VERSION 5.4 ;
NAMESCASESENSITIVE ON ;
BUSBITCHARS "[]" ;
DIVIDERCHAR "/" ;
UNITS
  DATABASE MICRONS 2000 ;
END UNITS
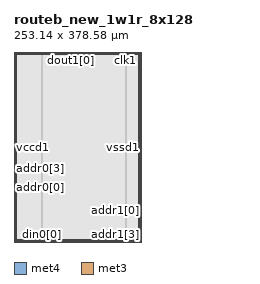
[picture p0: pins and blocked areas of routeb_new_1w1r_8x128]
MACRO routeb_new_1w1r_8x128
   CLASS BLOCK ;
   SIZE 253.14 BY 378.58 ;
   SYMMETRY X Y R90 ;
   PIN din0[0]
      DIRECTION INPUT ;
      PORT
         LAYER met4 ;
         RECT  56.02 0.0 56.4 0.38 ;
      END
   END din0[0]
   PIN din0[1]
      DIRECTION INPUT ;
      PORT
         LAYER met4 ;
         RECT  61.86 0.0 62.24 0.38 ;
      END
   END din0[1]
   PIN din0[2]
      DIRECTION INPUT ;
      PORT
         LAYER met4 ;
         RECT  67.7 0.0 68.08 0.38 ;
      END
   END din0[2]
   PIN din0[3]
      DIRECTION INPUT ;
      PORT
         LAYER met4 ;
         RECT  73.54 0.0 73.92 0.38 ;
      END
   END din0[3]
   PIN din0[4]
      DIRECTION INPUT ;
      PORT
         LAYER met4 ;
         RECT  79.38 0.0 79.76 0.38 ;
      END
   END din0[4]
   PIN din0[5]
      DIRECTION INPUT ;
      PORT
         LAYER met4 ;
         RECT  85.22 0.0 85.6 0.38 ;
      END
   END din0[5]
   PIN din0[6]
      DIRECTION INPUT ;
      PORT
         LAYER met4 ;
         RECT  91.06 0.0 91.44 0.38 ;
      END
   END din0[6]
   PIN din0[7]
      DIRECTION INPUT ;
      PORT
         LAYER met4 ;
         RECT  96.9 0.0 97.28 0.38 ;
      END
   END din0[7]
   PIN addr0[0]
      DIRECTION INPUT ;
      PORT
         LAYER met3 ;
         RECT  0.0 108.68 0.38 109.06 ;
      END
   END addr0[0]
   PIN addr0[1]
      DIRECTION INPUT ;
      PORT
         LAYER met3 ;
         RECT  0.0 117.18 0.38 117.56 ;
      END
   END addr0[1]
   PIN addr0[2]
      DIRECTION INPUT ;
      PORT
         LAYER met3 ;
         RECT  0.0 122.82 0.38 123.2 ;
      END
   END addr0[2]
   PIN addr0[3]
      DIRECTION INPUT ;
      PORT
         LAYER met3 ;
         RECT  0.0 131.32 0.38 131.7 ;
      END
   END addr0[3]
   PIN addr0[4]
      DIRECTION INPUT ;
      PORT
         LAYER met3 ;
         RECT  0.0 136.96 0.38 137.34 ;
      END
   END addr0[4]
   PIN addr0[5]
      DIRECTION INPUT ;
      PORT
         LAYER met3 ;
         RECT  0.0 145.46 0.38 145.84 ;
      END
   END addr0[5]
   PIN addr0[6]
      DIRECTION INPUT ;
      PORT
         LAYER met3 ;
         RECT  0.0 151.1 0.38 151.48 ;
      END
   END addr0[6]
   PIN addr1[0]
      DIRECTION INPUT ;
      PORT
         LAYER met3 ;
         RECT  252.76 63.54 253.14 63.92 ;
      END
   END addr1[0]
   PIN addr1[1]
      DIRECTION INPUT ;
      PORT
         LAYER met3 ;
         RECT  252.76 55.04 253.14 55.42 ;
      END
   END addr1[1]
   PIN addr1[2]
      DIRECTION INPUT ;
      PORT
         LAYER met3 ;
         RECT  252.76 49.4 253.14 49.78 ;
      END
   END addr1[2]
   PIN addr1[3]
      DIRECTION INPUT ;
      PORT
         LAYER met4 ;
         RECT  209.96 0.0 210.34 0.38 ;
      END
   END addr1[3]
   PIN addr1[4]
      DIRECTION INPUT ;
      PORT
         LAYER met4 ;
         RECT  206.985 0.0 207.365 0.38 ;
      END
   END addr1[4]
   PIN addr1[5]
      DIRECTION INPUT ;
      PORT
         LAYER met4 ;
         RECT  207.675 0.0 208.055 0.38 ;
      END
   END addr1[5]
   PIN addr1[6]
      DIRECTION INPUT ;
      PORT
         LAYER met4 ;
         RECT  208.42 0.0 208.8 0.38 ;
      END
   END addr1[6]
   PIN csb0
      DIRECTION INPUT ;
      PORT
         LAYER met3 ;
         RECT  0.0 14.87 0.38 15.25 ;
      END
   END csb0
   PIN csb1
      DIRECTION INPUT ;
      PORT
         LAYER met3 ;
         RECT  252.76 363.33 253.14 363.71 ;
      END
   END csb1
   PIN clk0
      DIRECTION INPUT ;
      PORT
         LAYER met4 ;
         RECT  30.26 0.0 30.64 0.38 ;
      END
   END clk0
   PIN clk1
      DIRECTION INPUT ;
      PORT
         LAYER met4 ;
         RECT  222.5 378.2 222.88 378.58 ;
      END
   END clk1
   PIN dout1[0]
      DIRECTION OUTPUT ;
      PORT
         LAYER met4 ;
         RECT  114.325 378.2 114.705 378.58 ;
      END
   END dout1[0]
   PIN dout1[1]
      DIRECTION OUTPUT ;
      PORT
         LAYER met4 ;
         RECT  119.295 378.2 119.675 378.58 ;
      END
   END dout1[1]
   PIN dout1[2]
      DIRECTION OUTPUT ;
      PORT
         LAYER met4 ;
         RECT  120.565 378.2 120.945 378.58 ;
      END
   END dout1[2]
   PIN dout1[3]
      DIRECTION OUTPUT ;
      PORT
         LAYER met4 ;
         RECT  125.535 378.2 125.915 378.58 ;
      END
   END dout1[3]
   PIN dout1[4]
      DIRECTION OUTPUT ;
      PORT
         LAYER met4 ;
         RECT  126.805 378.2 127.185 378.58 ;
      END
   END dout1[4]
   PIN dout1[5]
      DIRECTION OUTPUT ;
      PORT
         LAYER met4 ;
         RECT  131.775 378.2 132.155 378.58 ;
      END
   END dout1[5]
   PIN dout1[6]
      DIRECTION OUTPUT ;
      PORT
         LAYER met4 ;
         RECT  133.045 378.2 133.425 378.58 ;
      END
   END dout1[6]
   PIN dout1[7]
      DIRECTION OUTPUT ;
      PORT
         LAYER met4 ;
         RECT  138.015 378.2 138.395 378.58 ;
      END
   END dout1[7]
   PIN vccd1
      DIRECTION INOUT ;
      USE POWER ; 
      SHAPE ABUTMENT ; 
      PORT
         LAYER met3 ;
         RECT  0.0 376.84 253.14 378.58 ;
         LAYER met4 ;
         RECT  0.0 0.0 1.74 378.58 ;
         LAYER met4 ;
         RECT  251.4 0.0 253.14 378.58 ;
         LAYER met3 ;
         RECT  0.0 0.0 253.14 1.74 ;
      END
   END vccd1
   PIN vssd1
      DIRECTION INOUT ;
      USE GROUND ; 
      SHAPE ABUTMENT ; 
      PORT
         LAYER met3 ;
         RECT  3.48 3.48 249.66 5.22 ;
         LAYER met4 ;
         RECT  247.92 3.48 249.66 375.1 ;
         LAYER met3 ;
         RECT  3.48 373.36 249.66 375.1 ;
         LAYER met4 ;
         RECT  3.48 3.48 5.22 375.1 ;
      END
   END vssd1
   OBS
   LAYER  met1 ;
      RECT  0.62 0.62 252.52 377.96 ;
   LAYER  met2 ;
      RECT  0.62 0.62 252.52 377.96 ;
   LAYER  met3 ;
      RECT  0.98 108.08 252.52 109.66 ;
      RECT  0.62 109.66 0.98 116.58 ;
      RECT  0.62 118.16 0.98 122.22 ;
      RECT  0.62 123.8 0.98 130.72 ;
      RECT  0.62 132.3 0.98 136.36 ;
      RECT  0.62 137.94 0.98 144.86 ;
      RECT  0.62 146.44 0.98 150.5 ;
      RECT  0.98 62.94 252.16 64.52 ;
      RECT  0.98 64.52 252.16 108.08 ;
      RECT  252.16 64.52 252.52 108.08 ;
      RECT  252.16 56.02 252.52 62.94 ;
      RECT  252.16 50.38 252.52 54.44 ;
      RECT  0.62 15.85 0.98 108.08 ;
      RECT  0.98 109.66 252.16 362.73 ;
      RECT  0.98 362.73 252.16 364.31 ;
      RECT  252.16 109.66 252.52 362.73 ;
      RECT  0.62 152.08 0.98 376.24 ;
      RECT  252.16 364.31 252.52 376.24 ;
      RECT  252.16 2.34 252.52 48.8 ;
      RECT  0.62 2.34 0.98 14.27 ;
      RECT  0.98 2.34 2.88 2.88 ;
      RECT  0.98 2.88 2.88 5.82 ;
      RECT  0.98 5.82 2.88 62.94 ;
      RECT  2.88 2.34 250.26 2.88 ;
      RECT  2.88 5.82 250.26 62.94 ;
      RECT  250.26 2.34 252.16 2.88 ;
      RECT  250.26 2.88 252.16 5.82 ;
      RECT  250.26 5.82 252.16 62.94 ;
      RECT  0.98 364.31 2.88 372.76 ;
      RECT  0.98 372.76 2.88 375.7 ;
      RECT  0.98 375.7 2.88 376.24 ;
      RECT  2.88 364.31 250.26 372.76 ;
      RECT  2.88 375.7 250.26 376.24 ;
      RECT  250.26 364.31 252.16 372.76 ;
      RECT  250.26 372.76 252.16 375.7 ;
      RECT  250.26 375.7 252.16 376.24 ;
   LAYER  met4 ;
      RECT  55.42 0.98 57.0 377.96 ;
      RECT  57.0 0.62 61.26 0.98 ;
      RECT  62.84 0.62 67.1 0.98 ;
      RECT  68.68 0.62 72.94 0.98 ;
      RECT  74.52 0.62 78.78 0.98 ;
      RECT  80.36 0.62 84.62 0.98 ;
      RECT  86.2 0.62 90.46 0.98 ;
      RECT  92.04 0.62 96.3 0.98 ;
      RECT  97.88 0.62 206.385 0.98 ;
      RECT  31.24 0.62 55.42 0.98 ;
      RECT  57.0 0.98 221.9 377.6 ;
      RECT  221.9 0.98 223.48 377.6 ;
      RECT  57.0 377.6 113.725 377.96 ;
      RECT  115.305 377.6 118.695 377.96 ;
      RECT  121.545 377.6 124.935 377.96 ;
      RECT  127.785 377.6 131.175 377.96 ;
      RECT  134.025 377.6 137.415 377.96 ;
      RECT  138.995 377.6 221.9 377.96 ;
      RECT  2.34 0.62 29.66 0.98 ;
      RECT  210.94 0.62 250.8 0.98 ;
      RECT  223.48 377.6 250.8 377.96 ;
      RECT  223.48 0.98 247.32 2.88 ;
      RECT  223.48 2.88 247.32 375.7 ;
      RECT  223.48 375.7 247.32 377.6 ;
      RECT  247.32 0.98 250.26 2.88 ;
      RECT  247.32 375.7 250.26 377.6 ;
      RECT  250.26 0.98 250.8 2.88 ;
      RECT  250.26 2.88 250.8 375.7 ;
      RECT  250.26 375.7 250.8 377.6 ;
      RECT  2.34 0.98 2.88 2.88 ;
      RECT  2.34 2.88 2.88 375.7 ;
      RECT  2.34 375.7 2.88 377.96 ;
      RECT  2.88 0.98 5.82 2.88 ;
      RECT  2.88 375.7 5.82 377.96 ;
      RECT  5.82 0.98 55.42 2.88 ;
      RECT  5.82 2.88 55.42 375.7 ;
      RECT  5.82 375.7 55.42 377.96 ;
   END
END    routeb_new_1w1r_8x128
END    LIBRARY
